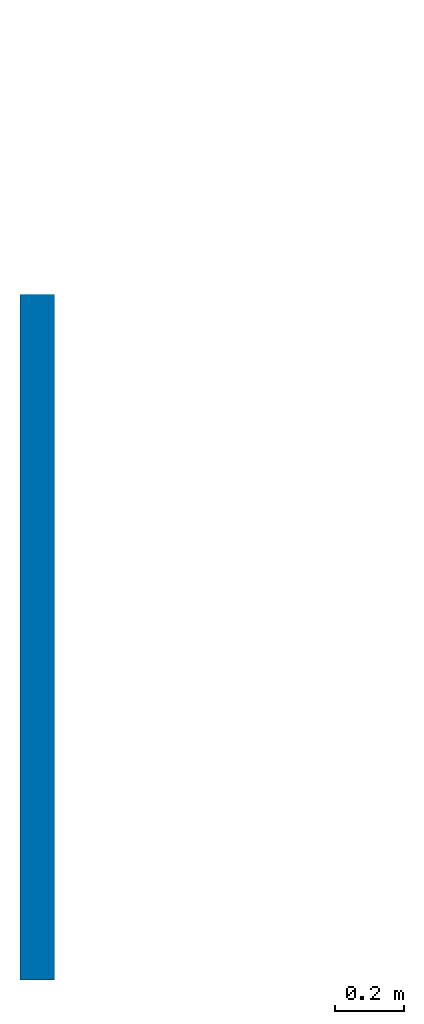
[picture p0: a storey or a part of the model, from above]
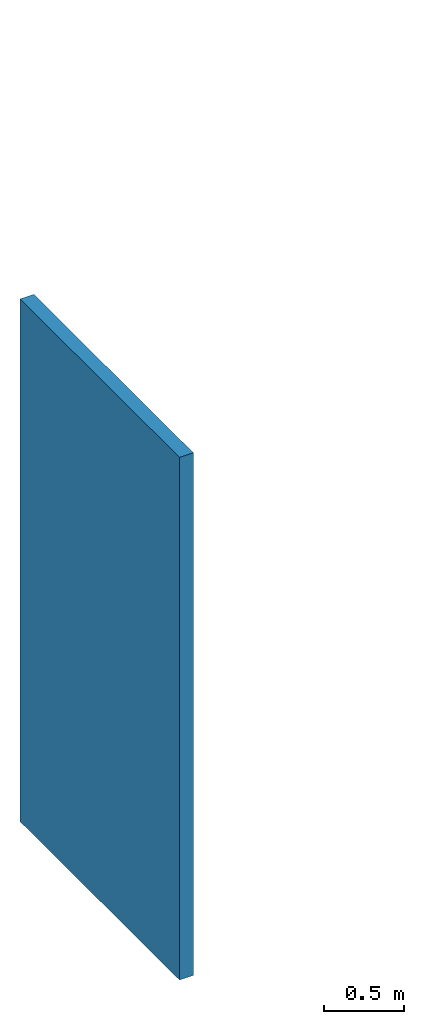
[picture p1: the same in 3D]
Properties of the parts of a building model (IFC2X3)

# File
Description: ViewDefinition [CoordinationView_V2.0]
File name: 0001
Time: 2022-01-20T15:56:10
Written by: The EXPRESS Data Manager Version 5.02.0100.07 : 28 Aug 2013
Made in: 22.0.2.392 - Exporter 22.0.2.392 - Alternate UI 22.0.2.392

# IfcProject, 0001
LongName: Project Name; Phase: Project Status

# IfcSite, Default
RefLatitude: 42, 21, 31, 181945; RefLongitude: -71, -3, -24, -263305; RefElevation: 0 mm
Pset_ProductRequirements - Category: Project Information

# IfcBuilding
Pset_BuildingCommon - NumberOfStoreys: 1
Pset_ProductRequirements - Category: Project Information

# IfcBuildingStorey: Level:8mm Head, Level 1
LongName: Level 1; Elevation: 0 mm
Pset_AirSideSystemInformation - Name: Level 1
Pset_ProductRequirements - Name: Level 1; Category: Levels

# IfcWallStandardCase: Basic Wall:Generic - 100mm (2)
In: Level 1
Type - PredefinedType: STANDARD; Material: Default Wall 100 mm
Type - Pset_ElementShading - Roughness: 914.4 mm
Type - Pset_ProductRequirements - Category: Walls
Type - Pset_WallCommon - IsExternal: yes
Pset_QuantityTakeOff - Reference: Generic - 100mm; sets with these values: 2
Pset_WallCommon - Reference: Generic - 100mm; ExtendToStructure: no; LoadBearing: no
Name (Basic Wall:Generic - 100mm:...)
348768
349070
